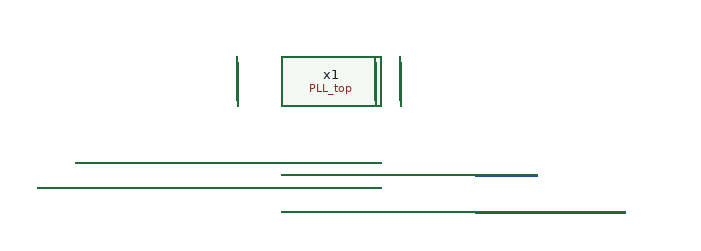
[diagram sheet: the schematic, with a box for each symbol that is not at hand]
v {xschem version=3.4.8RC file_version=1.3}
G {}
K {}
V {}
S {}
F {}
E {}
N 150 -10 200 -10 {lab=#net1}
N -170 -20 -90 -20 {lab=#net2}
N -200 0 -90 -0 {lab=#net3}
N 150 20 270 20 {lab=#net4}
N 90 -100 90 -70 {lab=#net5}
N 70 -100 70 -70 {lab=#net6}
N -40 -100 -40 -70 {lab=#net7}
C {PLL_top.sym} 60 -80 0 0 {name=x1}
